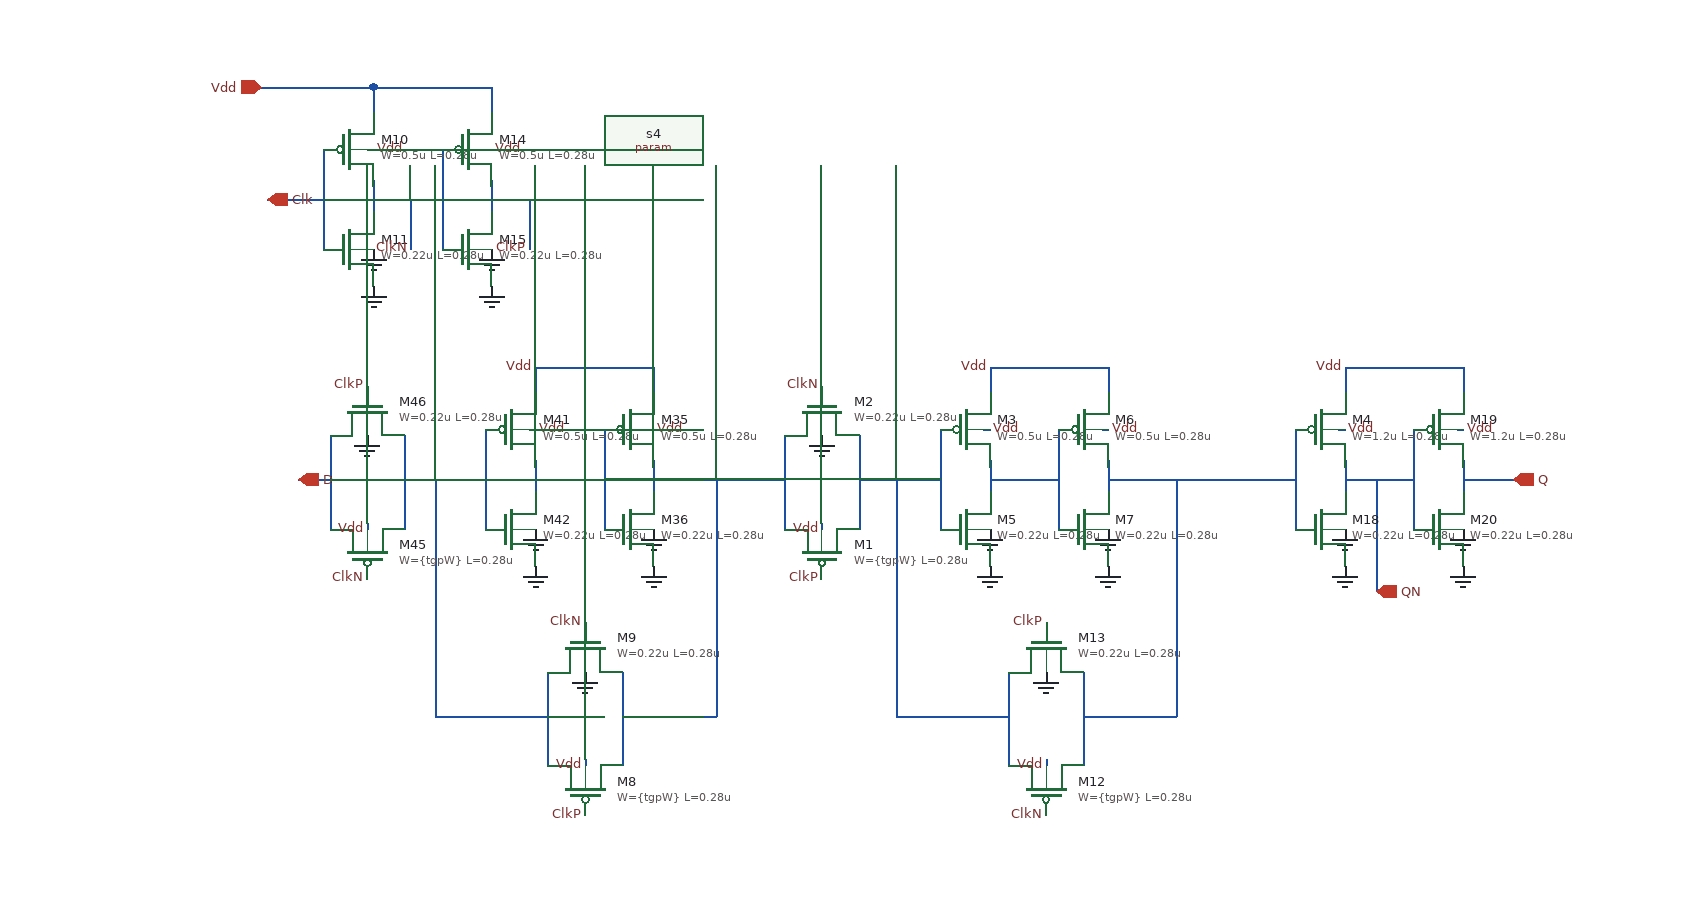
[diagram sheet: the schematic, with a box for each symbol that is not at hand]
v {xschem version=3.4.8RC file_version=1.3}
G {}
K {}
V {}
S {}
F {}
E {}
N -90 35 -85 35 {lab=Vdd}
N -85 70 -85 85 {lab=#net1}
N -85 60 -85 70 {lab=#net1}
N -125 35 -125 115 {lab=#net2}
N -85 -15 -85 5 {lab=Vdd}
N -220 110 -220 115 {lab=Vdd}
N -170 75 -140 75 {lab=#net2}
N -85 75 -45 75 {lab=#net1}
N 5 35 10 35 {lab=Vdd}
N 10 70 10 85 {lab=#net3}
N 10 60 10 70 {lab=#net3}
N -30 35 -30 115 {lab=#net1}
N 10 75 50 75 {lab=#net3}
N -250 40 -250 115 {lab=D}
N -190 40 -190 115 {lab=#net2}
N -190 75 -170 75 {lab=#net2}
N 10 -15 10 0 {lab=Vdd}
N 10 0 10 5 {lab=Vdd}
N -165 75 -165 180 {lab=#net2}
N 145 110 145 115 {lab=Vdd}
N 115 40 115 115 {lab=#net3}
N 175 40 175 115 {lab=#net4}
N 50 75 115 75 {lab=#net3}
N 175 75 195 75 {lab=#net4}
N -45 75 -30 75 {lab=#net1}
N -140 75 -125 75 {lab=#net2}
N -85 -15 10 -15 {lab=Vdd}
N 275 35 280 35 {lab=Vdd}
N 280 70 280 85 {lab=#net5}
N 280 60 280 70 {lab=#net5}
N 240 35 240 115 {lab=#net4}
N 195 75 225 75 {lab=#net4}
N 280 75 320 75 {lab=#net5}
N 370 35 375 35 {lab=Vdd}
N 375 70 375 85 {lab=#net6}
N 375 60 375 70 {lab=#net6}
N 335 35 335 115 {lab=#net5}
N 375 75 415 75 {lab=#net6}
N 375 -15 375 0 {lab=Vdd}
N 375 0 375 5 {lab=Vdd}
N 415 75 480 75 {lab=#net6}
N 320 75 335 75 {lab=#net5}
N 225 75 240 75 {lab=#net4}
N 280 -15 375 -15 {lab=Vdd}
N 60 145 60 250 {lab=#net3}
N -45 300 -45 305 {lab=Vdd}
N -75 230 -75 305 {lab=#net2}
N -15 230 -15 305 {lab=#net3}
N -140 265 -75 265 {lab=#net2}
N -15 265 5 265 {lab=#net3}
N -165 180 -165 265 {lab=#net2}
N -165 265 -140 265 {lab=#net2}
N 60 75 60 145 {lab=#net3}
N 60 250 60 260 {lab=#net3}
N 60 260 60 265 {lab=#net3}
N 5 265 60 265 {lab=#net3}
N 205 75 205 180 {lab=#net4}
N 430 145 430 250 {lab=#net6}
N 325 300 325 305 {lab=Vdd}
N 295 230 295 305 {lab=#net4}
N 355 230 355 305 {lab=#net6}
N 230 265 295 265 {lab=#net4}
N 355 265 375 265 {lab=#net6}
N 205 180 205 265 {lab=#net4}
N 205 265 230 265 {lab=#net4}
N 430 250 430 260 {lab=#net6}
N 430 260 430 265 {lab=#net6}
N 375 265 430 265 {lab=#net6}
N 430 75 430 145 {lab=#net6}
N -220 -190 -215 -190 {lab=Vdd}
N -215 -155 -215 -140 {lab=ClkN}
N -215 -165 -215 -155 {lab=ClkN}
N -255 -190 -255 -110 {lab=Clk}
N -215 -240 -215 -220 {lab=Vdd}
N -300 -150 -270 -150 {lab=Clk}
N -215 -150 -175 -150 {lab=ClkN}
N -125 -190 -120 -190 {lab=Vdd}
N -120 -155 -120 -140 {lab=ClkP}
N -120 -165 -120 -155 {lab=ClkP}
N -160 -190 -160 -110 {lab=ClkN}
N -120 -240 -120 -225 {lab=Vdd}
N -120 -225 -120 -220 {lab=Vdd}
N -175 -150 -160 -150 {lab=ClkN}
N -270 -150 -255 -150 {lab=Clk}
N -275 75 -250 75 {lab=D}
N -185 -150 -185 -110 {lab=ClkN}
N -90 -150 -90 -110 {lab=ClkP}
N 280 -15 280 5 {lab=Vdd}
N 560 35 565 35 {lab=Vdd}
N 565 70 565 85 {lab=QN}
N 565 60 565 70 {lab=QN}
N 525 35 525 115 {lab=#net6}
N 480 75 510 75 {lab=#net6}
N 565 75 605 75 {lab=QN}
N 655 35 660 35 {lab=Vdd}
N 660 70 660 85 {lab=Q}
N 660 60 660 70 {lab=Q}
N 620 35 620 115 {lab=QN}
N 660 75 700 75 {lab=Q}
N 660 -15 660 0 {lab=Vdd}
N 660 0 660 5 {lab=Vdd}
N 605 75 620 75 {lab=QN}
N 510 75 525 75 {lab=#net6}
N 565 -15 565 5 {lab=Vdd}
N 565 -15 660 -15 {lab=Vdd}
N -305 -240 -215 -240 {lab=Vdd}
N 590 75 590 165 {lab=QN}
N -215 -240 -120 -240 {lab=Vdd}
N -120 -150 -90 -150 {lab=ClkP}
C {symbols/pfet_03v3.sym} -105 35 0 0 {name=M41
L=0.28u
W=0.5u
nf=1
m=1
ad="'int((nf+1)/2) * W/nf * 0.18u'"
pd="'2*int((nf+1)/2) * (W/nf + 0.18u)'"
as="'int((nf+2)/2) * W/nf * 0.18u'"
ps="'2*int((nf+2)/2) * (W/nf + 0.18u)'"
nrd="'0.18u / W'" nrs="'0.18u / W'"
sa=0 sb=0 sd=0
model=pfet_03v3
spiceprefix=X
}
C {lab_pin.sym} -85 35 0 1 {name=p92 sig_type=std_logic lab=Vdd}
C {gnd.sym} -85 115 3 0 {name=l27 lab=0}
C {symbols/nfet_03v3.sym} -105 115 0 0 {name=M42
L=0.28u
W=0.22u
nf=1
m=1
ad="'int((nf+1)/2) * W/nf * 0.18u'"
pd="'2*int((nf+1)/2) * (W/nf + 0.18u)'"
as="'int((nf+2)/2) * W/nf * 0.18u'"
ps="'2*int((nf+2)/2) * (W/nf + 0.18u)'"
nrd="'0.18u / W'" nrs="'0.18u / W'"
sa=0 sb=0 sd=0
model=nfet_03v3
spiceprefix=X
}
C {gnd.sym} -85 145 0 1 {name=l28 lab=0}
C {symbols/pfet_03v3.sym} -220 135 1 1 {name=M45
L=0.28u
W=\{tgpW\}
nf=1
m=1
ad="'int((nf+1)/2) * W/nf * 0.18u'"
pd="'2*int((nf+1)/2) * (W/nf + 0.18u)'"
as="'int((nf+2)/2) * W/nf * 0.18u'"
ps="'2*int((nf+2)/2) * (W/nf + 0.18u)'"
nrd="'0.18u / W'" nrs="'0.18u / W'"
sa=0 sb=0 sd=0
model=pfet_03v3
spiceprefix=X
}
C {symbols/nfet_03v3.sym} -220 20 3 1 {name=M46
L=0.28u
W=0.22u
nf=1
m=1
ad="'int((nf+1)/2) * W/nf * 0.18u'"
pd="'2*int((nf+1)/2) * (W/nf + 0.18u)'"
as="'int((nf+2)/2) * W/nf * 0.18u'"
ps="'2*int((nf+2)/2) * (W/nf + 0.18u)'"
nrd="'0.18u / W'" nrs="'0.18u / W'"
sa=0 sb=0 sd=0
model=nfet_03v3
spiceprefix=X
}
C {gnd.sym} -220 40 0 0 {name=l6 lab=0}
C {lab_pin.sym} -220 115 1 0 {name=p99 sig_type=std_logic lab=Vdd}
C {symbols/pfet_03v3.sym} -10 35 0 0 {name=M35
L=0.28u
W=0.5u
nf=1
m=1
ad="'int((nf+1)/2) * W/nf * 0.18u'"
pd="'2*int((nf+1)/2) * (W/nf + 0.18u)'"
as="'int((nf+2)/2) * W/nf * 0.18u'"
ps="'2*int((nf+2)/2) * (W/nf + 0.18u)'"
nrd="'0.18u / W'" nrs="'0.18u / W'"
sa=0 sb=0 sd=0
model=pfet_03v3
spiceprefix=X
}
C {lab_pin.sym} 10 35 0 1 {name=p80 sig_type=std_logic lab=Vdd}
C {gnd.sym} 10 115 3 0 {name=l13 lab=0}
C {symbols/nfet_03v3.sym} -10 115 0 0 {name=M36
L=0.28u
W=0.22u
nf=1
m=1
ad="'int((nf+1)/2) * W/nf * 0.18u'"
pd="'2*int((nf+1)/2) * (W/nf + 0.18u)'"
as="'int((nf+2)/2) * W/nf * 0.18u'"
ps="'2*int((nf+2)/2) * (W/nf + 0.18u)'"
nrd="'0.18u / W'" nrs="'0.18u / W'"
sa=0 sb=0 sd=0
model=nfet_03v3
spiceprefix=X
}
C {gnd.sym} 10 145 0 1 {name=l20 lab=0}
C {ipin.sym} -300 -150 2 1 {name=p1 lab=Clk}
C {ipin.sym} -305 -240 0 0 {name=p3 lab=Vdd}
C {opin.sym} 700 75 0 0 {name=p4 lab=Q}
C {ipin.sym} -275 75 2 1 {name=p6 lab=D}
C {symbols/pfet_03v3.sym} 145 135 1 1 {name=M1
L=0.28u
W=\{tgpW\}
nf=1
m=1
ad="'int((nf+1)/2) * W/nf * 0.18u'"
pd="'2*int((nf+1)/2) * (W/nf + 0.18u)'"
as="'int((nf+2)/2) * W/nf * 0.18u'"
ps="'2*int((nf+2)/2) * (W/nf + 0.18u)'"
nrd="'0.18u / W'" nrs="'0.18u / W'"
sa=0 sb=0 sd=0
model=pfet_03v3
spiceprefix=X
}
C {symbols/nfet_03v3.sym} 145 20 3 1 {name=M2
L=0.28u
W=0.22u
nf=1
m=1
ad="'int((nf+1)/2) * W/nf * 0.18u'"
pd="'2*int((nf+1)/2) * (W/nf + 0.18u)'"
as="'int((nf+2)/2) * W/nf * 0.18u'"
ps="'2*int((nf+2)/2) * (W/nf + 0.18u)'"
nrd="'0.18u / W'" nrs="'0.18u / W'"
sa=0 sb=0 sd=0
model=nfet_03v3
spiceprefix=X
}
C {gnd.sym} 145 40 0 0 {name=l3 lab=0}
C {lab_pin.sym} 145 115 1 0 {name=p8 sig_type=std_logic lab=Vdd}
C {lab_pin.sym} 145 0 2 1 {name=p9 sig_type=std_logic lab=ClkN}
C {lab_pin.sym} 145 155 2 1 {name=p10 sig_type=std_logic lab=ClkP}
C {symbols/pfet_03v3.sym} 260 35 0 0 {name=M3
L=0.28u
W=0.5u
nf=1
m=1
ad="'int((nf+1)/2) * W/nf * 0.18u'"
pd="'2*int((nf+1)/2) * (W/nf + 0.18u)'"
as="'int((nf+2)/2) * W/nf * 0.18u'"
ps="'2*int((nf+2)/2) * (W/nf + 0.18u)'"
nrd="'0.18u / W'" nrs="'0.18u / W'"
sa=0 sb=0 sd=0
model=pfet_03v3
spiceprefix=X
}
C {lab_pin.sym} 280 35 0 1 {name=p12 sig_type=std_logic lab=Vdd}
C {gnd.sym} 280 115 3 0 {name=l5 lab=0}
C {symbols/nfet_03v3.sym} 260 115 0 0 {name=M5
L=0.28u
W=0.22u
nf=1
m=1
ad="'int((nf+1)/2) * W/nf * 0.18u'"
pd="'2*int((nf+1)/2) * (W/nf + 0.18u)'"
as="'int((nf+2)/2) * W/nf * 0.18u'"
ps="'2*int((nf+2)/2) * (W/nf + 0.18u)'"
nrd="'0.18u / W'" nrs="'0.18u / W'"
sa=0 sb=0 sd=0
model=nfet_03v3
spiceprefix=X
}
C {gnd.sym} 280 145 0 1 {name=l7 lab=0}
C {symbols/pfet_03v3.sym} 355 35 0 0 {name=M6
L=0.28u
W=0.5u
nf=1
m=1
ad="'int((nf+1)/2) * W/nf * 0.18u'"
pd="'2*int((nf+1)/2) * (W/nf + 0.18u)'"
as="'int((nf+2)/2) * W/nf * 0.18u'"
ps="'2*int((nf+2)/2) * (W/nf + 0.18u)'"
nrd="'0.18u / W'" nrs="'0.18u / W'"
sa=0 sb=0 sd=0
model=pfet_03v3
spiceprefix=X
}
C {lab_pin.sym} 375 35 0 1 {name=p14 sig_type=std_logic lab=Vdd}
C {gnd.sym} 375 115 3 0 {name=l8 lab=0}
C {symbols/nfet_03v3.sym} 355 115 0 0 {name=M7
L=0.28u
W=0.22u
nf=1
m=1
ad="'int((nf+1)/2) * W/nf * 0.18u'"
pd="'2*int((nf+1)/2) * (W/nf + 0.18u)'"
as="'int((nf+2)/2) * W/nf * 0.18u'"
ps="'2*int((nf+2)/2) * (W/nf + 0.18u)'"
nrd="'0.18u / W'" nrs="'0.18u / W'"
sa=0 sb=0 sd=0
model=nfet_03v3
spiceprefix=X
}
C {gnd.sym} 375 145 0 1 {name=l9 lab=0}
C {symbols/pfet_03v3.sym} -45 325 1 1 {name=M8
L=0.28u
W=\{tgpW\}
nf=1
m=1
ad="'int((nf+1)/2) * W/nf * 0.18u'"
pd="'2*int((nf+1)/2) * (W/nf + 0.18u)'"
as="'int((nf+2)/2) * W/nf * 0.18u'"
ps="'2*int((nf+2)/2) * (W/nf + 0.18u)'"
nrd="'0.18u / W'" nrs="'0.18u / W'"
sa=0 sb=0 sd=0
model=pfet_03v3
spiceprefix=X
}
C {symbols/nfet_03v3.sym} -45 210 3 1 {name=M9
L=0.28u
W=0.22u
nf=1
m=1
ad="'int((nf+1)/2) * W/nf * 0.18u'"
pd="'2*int((nf+1)/2) * (W/nf + 0.18u)'"
as="'int((nf+2)/2) * W/nf * 0.18u'"
ps="'2*int((nf+2)/2) * (W/nf + 0.18u)'"
nrd="'0.18u / W'" nrs="'0.18u / W'"
sa=0 sb=0 sd=0
model=nfet_03v3
spiceprefix=X
}
C {gnd.sym} -45 230 0 0 {name=l10 lab=0}
C {lab_pin.sym} -45 305 1 0 {name=p16 sig_type=std_logic lab=Vdd}
C {lab_pin.sym} -45 190 2 1 {name=p18 sig_type=std_logic lab=ClkN}
C {lab_pin.sym} -45 345 2 1 {name=p19 sig_type=std_logic lab=ClkP}
C {symbols/pfet_03v3.sym} 325 325 1 1 {name=M12
L=0.28u
W=\{tgpW\}
nf=1
m=1
ad="'int((nf+1)/2) * W/nf * 0.18u'"
pd="'2*int((nf+1)/2) * (W/nf + 0.18u)'"
as="'int((nf+2)/2) * W/nf * 0.18u'"
ps="'2*int((nf+2)/2) * (W/nf + 0.18u)'"
nrd="'0.18u / W'" nrs="'0.18u / W'"
sa=0 sb=0 sd=0
model=pfet_03v3
spiceprefix=X
}
C {symbols/nfet_03v3.sym} 325 210 3 1 {name=M13
L=0.28u
W=0.22u
nf=1
m=1
ad="'int((nf+1)/2) * W/nf * 0.18u'"
pd="'2*int((nf+1)/2) * (W/nf + 0.18u)'"
as="'int((nf+2)/2) * W/nf * 0.18u'"
ps="'2*int((nf+2)/2) * (W/nf + 0.18u)'"
nrd="'0.18u / W'" nrs="'0.18u / W'"
sa=0 sb=0 sd=0
model=nfet_03v3
spiceprefix=X
}
C {gnd.sym} 325 230 0 0 {name=l18 lab=0}
C {lab_pin.sym} 325 305 1 0 {name=p20 sig_type=std_logic lab=Vdd}
C {lab_pin.sym} 325 190 2 1 {name=p21 sig_type=std_logic lab=ClkP}
C {lab_pin.sym} 325 345 2 1 {name=p22 sig_type=std_logic lab=ClkN}
C {symbols/pfet_03v3.sym} -235 -190 0 0 {name=M10
L=0.28u
W=0.5u
nf=1
m=1
ad="'int((nf+1)/2) * W/nf * 0.18u'"
pd="'2*int((nf+1)/2) * (W/nf + 0.18u)'"
as="'int((nf+2)/2) * W/nf * 0.18u'"
ps="'2*int((nf+2)/2) * (W/nf + 0.18u)'"
nrd="'0.18u / W'" nrs="'0.18u / W'"
sa=0 sb=0 sd=0
model=pfet_03v3
spiceprefix=X
}
C {lab_pin.sym} -215 -190 0 1 {name=p17 sig_type=std_logic lab=Vdd}
C {gnd.sym} -215 -110 3 0 {name=l15 lab=0}
C {symbols/nfet_03v3.sym} -235 -110 0 0 {name=M11
L=0.28u
W=0.22u
nf=1
m=1
ad="'int((nf+1)/2) * W/nf * 0.18u'"
pd="'2*int((nf+1)/2) * (W/nf + 0.18u)'"
as="'int((nf+2)/2) * W/nf * 0.18u'"
ps="'2*int((nf+2)/2) * (W/nf + 0.18u)'"
nrd="'0.18u / W'" nrs="'0.18u / W'"
sa=0 sb=0 sd=0
model=nfet_03v3
spiceprefix=X
}
C {gnd.sym} -215 -80 0 1 {name=l19 lab=0}
C {symbols/pfet_03v3.sym} -140 -190 0 0 {name=M14
L=0.28u
W=0.5u
nf=1
m=1
ad="'int((nf+1)/2) * W/nf * 0.18u'"
pd="'2*int((nf+1)/2) * (W/nf + 0.18u)'"
as="'int((nf+2)/2) * W/nf * 0.18u'"
ps="'2*int((nf+2)/2) * (W/nf + 0.18u)'"
nrd="'0.18u / W'" nrs="'0.18u / W'"
sa=0 sb=0 sd=0
model=pfet_03v3
spiceprefix=X
}
C {lab_pin.sym} -120 -190 0 1 {name=p23 sig_type=std_logic lab=Vdd}
C {gnd.sym} -120 -110 3 0 {name=l24 lab=0}
C {symbols/nfet_03v3.sym} -140 -110 0 0 {name=M15
L=0.28u
W=0.22u
nf=1
m=1
ad="'int((nf+1)/2) * W/nf * 0.18u'"
pd="'2*int((nf+1)/2) * (W/nf + 0.18u)'"
as="'int((nf+2)/2) * W/nf * 0.18u'"
ps="'2*int((nf+2)/2) * (W/nf + 0.18u)'"
nrd="'0.18u / W'" nrs="'0.18u / W'"
sa=0 sb=0 sd=0
model=nfet_03v3
spiceprefix=X
}
C {gnd.sym} -120 -80 0 1 {name=l25 lab=0}
C {lab_pin.sym} -85 -15 2 1 {name=p24 sig_type=std_logic lab=Vdd}
C {lab_pin.sym} -185 -110 1 1 {name=p25 sig_type=std_logic lab=ClkN}
C {lab_pin.sym} -90 -110 1 1 {name=p26 sig_type=std_logic lab=ClkP}
C {lab_pin.sym} -220 0 2 1 {name=p27 sig_type=std_logic lab=ClkP}
C {lab_pin.sym} -220 155 2 1 {name=p28 sig_type=std_logic lab=ClkN}
C {lab_pin.sym} 280 -15 2 1 {name=p15 sig_type=std_logic lab=Vdd}
C {symbols/pfet_03v3.sym} 545 35 0 0 {name=M4
L=0.28u
W=1.2u
nf=1
m=1
ad="'int((nf+1)/2) * W/nf * 0.18u'"
pd="'2*int((nf+1)/2) * (W/nf + 0.18u)'"
as="'int((nf+2)/2) * W/nf * 0.18u'"
ps="'2*int((nf+2)/2) * (W/nf + 0.18u)'"
nrd="'0.18u / W'" nrs="'0.18u / W'"
sa=0 sb=0 sd=0
model=pfet_03v3
spiceprefix=X
}
C {lab_pin.sym} 565 35 0 1 {name=p2 sig_type=std_logic lab=Vdd}
C {gnd.sym} 565 115 3 0 {name=l2 lab=0}
C {symbols/nfet_03v3.sym} 545 115 0 0 {name=M18
L=0.28u
W=0.22u
nf=1
m=1
ad="'int((nf+1)/2) * W/nf * 0.18u'"
pd="'2*int((nf+1)/2) * (W/nf + 0.18u)'"
as="'int((nf+2)/2) * W/nf * 0.18u'"
ps="'2*int((nf+2)/2) * (W/nf + 0.18u)'"
nrd="'0.18u / W'" nrs="'0.18u / W'"
sa=0 sb=0 sd=0
model=nfet_03v3
spiceprefix=X
}
C {gnd.sym} 565 145 0 1 {name=l11 lab=0}
C {symbols/pfet_03v3.sym} 640 35 0 0 {name=M19
L=0.28u
W=1.2u
nf=1
m=1
ad="'int((nf+1)/2) * W/nf * 0.18u'"
pd="'2*int((nf+1)/2) * (W/nf + 0.18u)'"
as="'int((nf+2)/2) * W/nf * 0.18u'"
ps="'2*int((nf+2)/2) * (W/nf + 0.18u)'"
nrd="'0.18u / W'" nrs="'0.18u / W'"
sa=0 sb=0 sd=0
model=pfet_03v3
spiceprefix=X
}
C {lab_pin.sym} 660 35 0 1 {name=p5 sig_type=std_logic lab=Vdd}
C {gnd.sym} 660 115 3 0 {name=l12 lab=0}
C {symbols/nfet_03v3.sym} 640 115 0 0 {name=M20
L=0.28u
W=0.22u
nf=1
m=1
ad="'int((nf+1)/2) * W/nf * 0.18u'"
pd="'2*int((nf+1)/2) * (W/nf + 0.18u)'"
as="'int((nf+2)/2) * W/nf * 0.18u'"
ps="'2*int((nf+2)/2) * (W/nf + 0.18u)'"
nrd="'0.18u / W'" nrs="'0.18u / W'"
sa=0 sb=0 sd=0
model=nfet_03v3
spiceprefix=X
}
C {gnd.sym} 660 145 0 1 {name=l14 lab=0}
C {lab_pin.sym} 565 -15 2 1 {name=p11 sig_type=std_logic lab=Vdd}
C {param.sym} -425 215 0 0 {name=s4 value="tgpW=0.5u"}
C {opin.sym} 590 165 0 0 {name=p7 lab=QN}
